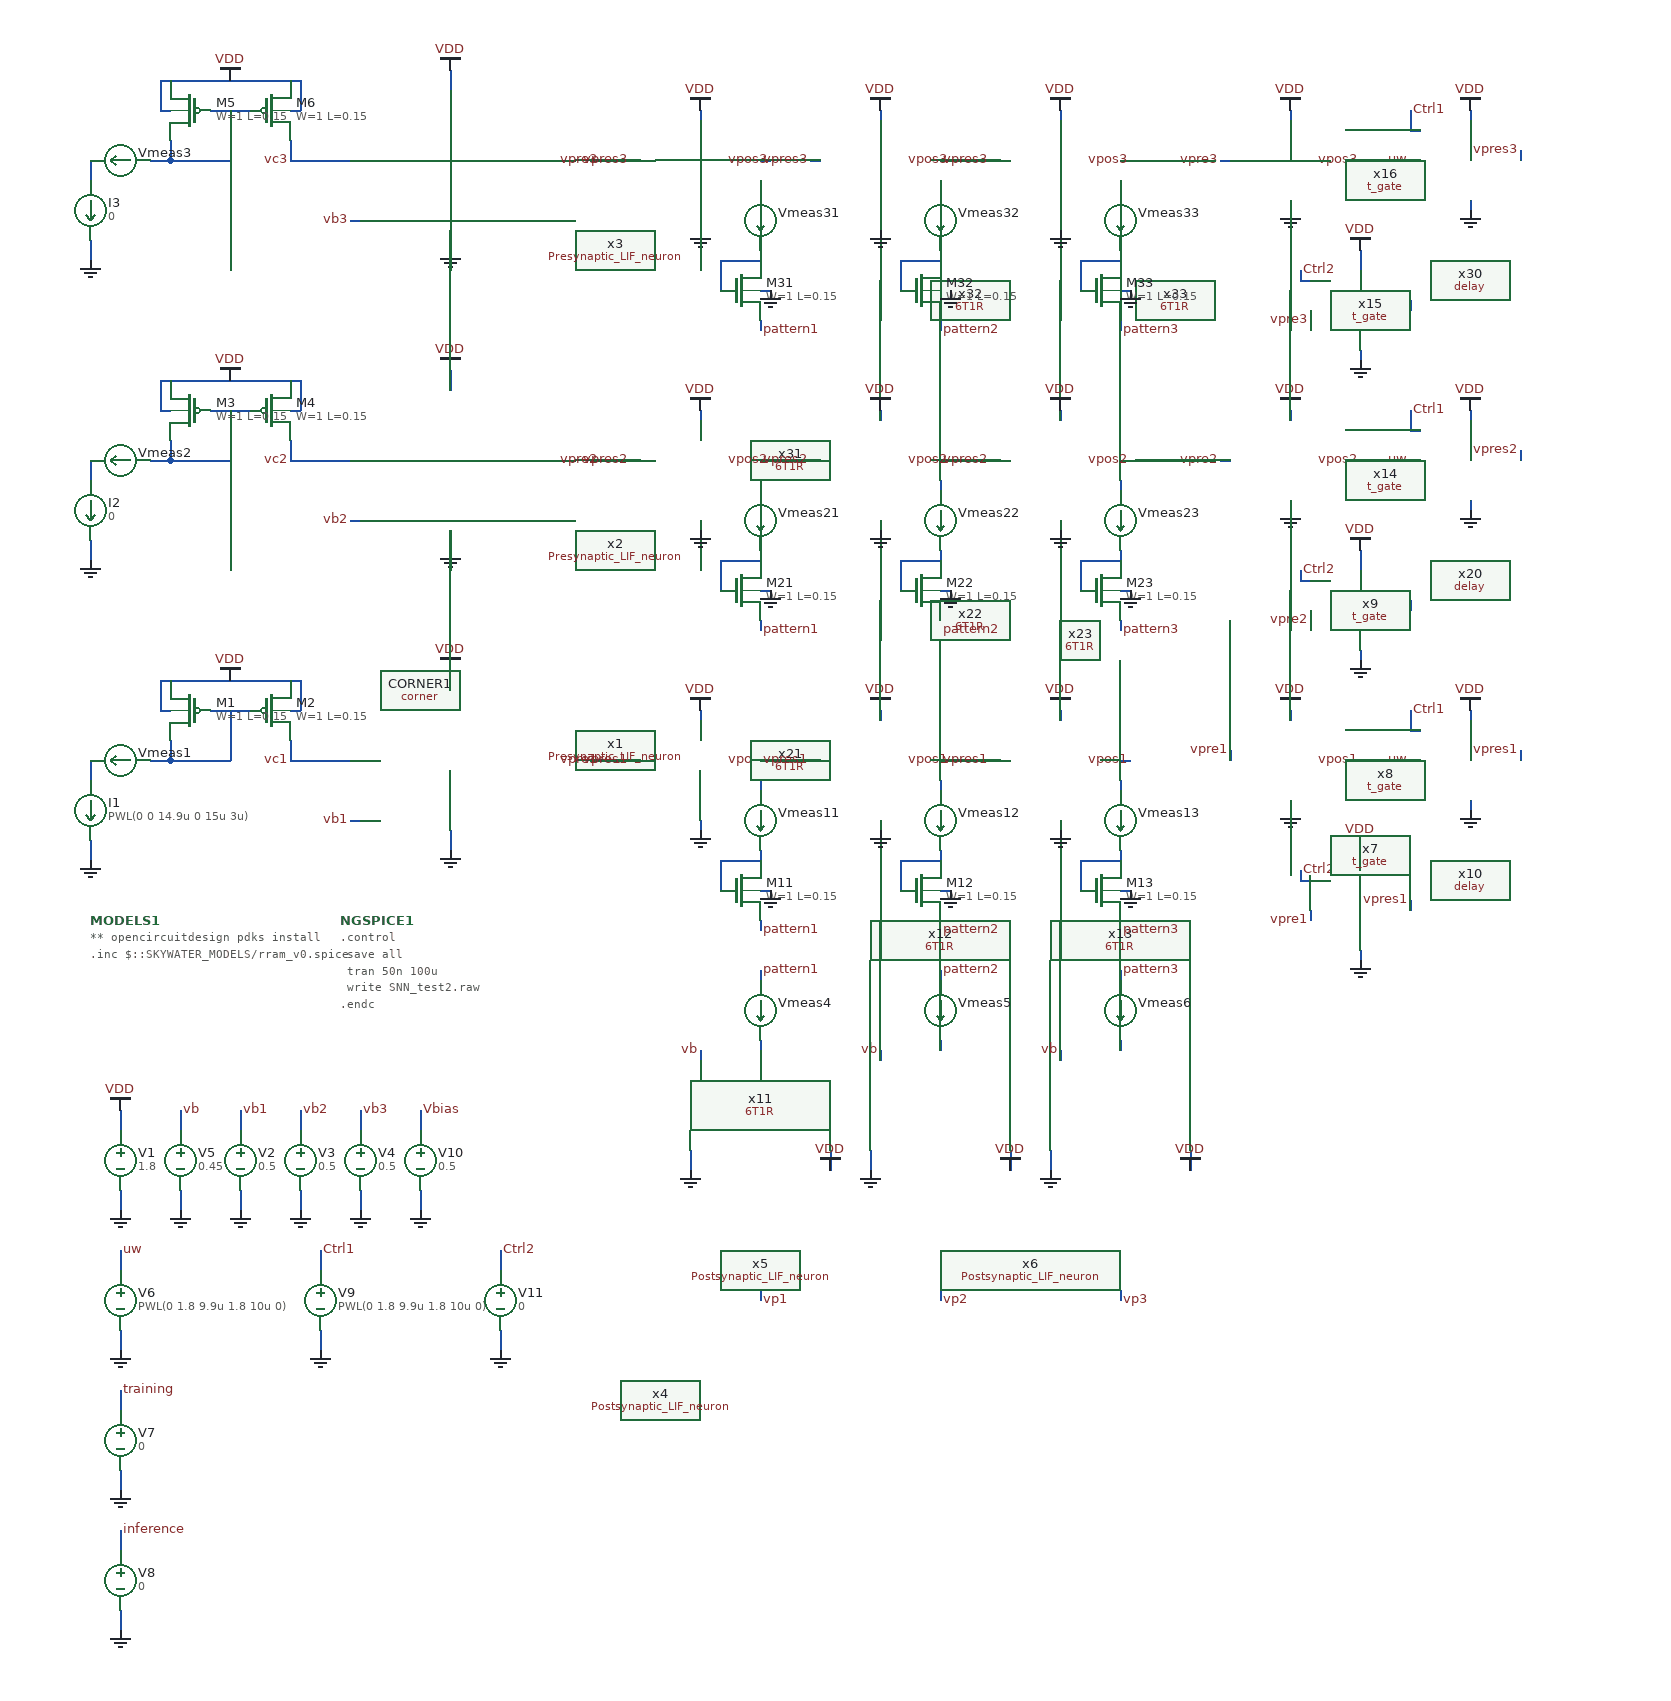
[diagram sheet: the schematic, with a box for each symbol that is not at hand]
v {xschem version=3.4.5 file_version=1.2
}
G {}
K {}
V {}
S {}
E {}
B 2 -1900 -1640 -1100 -1240 {flags=graph
y1=-0.081
y2=1.9
ypos1=0
ypos2=2
divy=5
subdivy=1
unity=1
x1=0
x2=0.0001
divx=5
subdivx=1
xlabmag=1.0
ylabmag=1.0
node="\\"Vpres1 [V];vpres1\\"
vpos1"
color="4 6"
dataset=-1
unitx=1
logx=0
logy=0
}
B 2 -1100 -1640 -300 -1240 {flags=graph
y1=5.1e-08
y2=3.4e-05
ypos1=0
ypos2=2
divy=5
subdivy=1
unity=1
x1=0
x2=0.0001
divx=5
subdivx=1
xlabmag=1.0
ylabmag=1.0


dataset=-1
unitx=1
logx=0
logy=0



color="4 10"
node="\\"Ipre1 (A);i(vmeas1)\\"
\\"Ipost (A);i(vmeas)\\""}
B 2 -1900 -1240 -1100 -840 {flags=graph
y1=0.023
y2=1.8
ypos1=0
ypos2=2
divy=5
subdivy=1
unity=1
x1=0
x2=0.0001
divx=5
subdivx=1
xlabmag=1.0
ylabmag=1.0


dataset=-1
unitx=1
logx=0
logy=0

color=4
node="\\"Vmempre1 [V];vc1\\""}
B 2 -1100 -1240 -300 -840 {flags=graph
y1=2.2
y2=3.4
ypos1=0
ypos2=2
divy=5
subdivy=1
unity=1
x1=0
x2=0.0001
divx=5
subdivx=1
xlabmag=1.0
ylabmag=1.0


dataset=-1
unitx=1
logx=0
logy=0




color=10
node="\\"Thickness1 [nm]; 5 n.x23.xr1.n1#ngap -\\""}
B 2 -1900 -840 -1100 -440 {flags=graph
y1=0
y2=1.8
ypos1=0
ypos2=2
divy=5
subdivy=1
unity=1
x1=0
x2=0.0001
divx=5
subdivx=1
xlabmag=1.0
ylabmag=1.0


dataset=-1
unitx=1
logx=0
logy=0
color="7 8 11 9"
node="\\"Update Weights;uw\\"
\\"Training;training\\"
\\"Inference;inference\\"
\\"e\\""}
B 2 -1100 -840 -300 -440 {flags=graph
y1=0
y2=0.01
ypos1=0
ypos2=2
divy=5
subdivy=1
unity=1
x1=0
x2=0.0001
divx=5
subdivx=1
xlabmag=1.0
ylabmag=1.0


dataset=-1
unitx=1
logx=0
logy=0

color="12 13 18"
node="\\"Pixel1;i(vmeas3)\\"
\\"Pixel2;i(vmeas3)\\"
\\"Pixel3;i(vmeas3)\\""}
N -3320 -530 -3320 -510 {
lab=GND}
N -3320 -610 -3320 -590 {
lab=VDD}
N -3200 -530 -3200 -510 {
lab=GND}
N -3200 -610 -3200 -590 {
lab=vb1}
N -2990 -890 -2990 -870 {
lab=GND}
N -2990 -1050 -2990 -1030 {
lab=VDD}
N -3090 -900 -3080 -900 {
lab=vb1}
N -3350 -880 -3350 -860 {
lab=GND}
N -3150 -980 -3150 -960 {
lab=vc1}
N -3150 -960 -3090 -960 {
lab=vc1}
N -3150 -1010 -3140 -1010 {
lab=VDD}
N -3140 -1040 -3140 -1010 {
lab=VDD}
N -3150 -1040 -3140 -1040 {
lab=VDD}
N -3230 -1010 -3190 -1010 {
lab=#net1}
N -3270 -1040 -3150 -1040 {
lab=VDD}
N -3280 -1010 -3270 -1010 {
lab=VDD}
N -3280 -1040 -3280 -1010 {
lab=VDD}
N -3280 -1040 -3270 -1040 {
lab=VDD}
N -3270 -980 -3270 -960 {
lab=#net1}
N -3270 -960 -3210 -960 {
lab=#net1}
N -3210 -1010 -3210 -960 {
lab=#net1}
N -3350 -960 -3350 -940 {
lab=#net2}
N -2560 -670 -2560 -660 {
lab=vb}
N -3140 -530 -3140 -510 {
lab=GND}
N -3140 -610 -3140 -590 {
lab=vb2}
N -3080 -530 -3080 -510 {
lab=GND}
N -3080 -610 -3080 -590 {
lab=vb3}
N -3260 -530 -3260 -510 {
lab=GND}
N -3260 -610 -3260 -590 {
lab=vb}
N -2990 -1190 -2990 -1170 {
lab=GND}
N -2990 -1350 -2990 -1330 {
lab=VDD}
N -3090 -1200 -3080 -1200 {
lab=vb2}
N -3150 -1260 -3090 -1260 {
lab=vc2}
N -3150 -1280 -3150 -1260 {
lab=vc2}
N -3150 -1310 -3140 -1310 {
lab=VDD}
N -3140 -1340 -3140 -1310 {
lab=VDD}
N -3150 -1340 -3140 -1340 {
lab=VDD}
N -3230 -1310 -3190 -1310 {
lab=#net3}
N -3270 -1340 -3150 -1340 {
lab=VDD}
N -3280 -1310 -3270 -1310 {
lab=VDD}
N -3280 -1340 -3280 -1310 {
lab=VDD}
N -3280 -1340 -3270 -1340 {
lab=VDD}
N -3270 -1280 -3270 -1260 {
lab=#net3}
N -3270 -1260 -3210 -1260 {
lab=#net3}
N -3210 -1310 -3210 -1260 {
lab=#net3}
N -2990 -1490 -2990 -1470 {
lab=GND}
N -2990 -1650 -2990 -1630 {
lab=VDD}
N -3090 -1500 -3080 -1500 {
lab=vb3}
N -3150 -1560 -3090 -1560 {
lab=vc3}
N -3150 -1580 -3150 -1560 {
lab=vc3}
N -3150 -1610 -3140 -1610 {
lab=VDD}
N -3140 -1640 -3140 -1610 {
lab=VDD}
N -3150 -1640 -3140 -1640 {
lab=VDD}
N -3230 -1610 -3190 -1610 {
lab=#net4}
N -3270 -1640 -3150 -1640 {
lab=VDD}
N -3280 -1610 -3270 -1610 {
lab=VDD}
N -3280 -1640 -3280 -1610 {
lab=VDD}
N -3280 -1640 -3270 -1640 {
lab=VDD}
N -3270 -1580 -3270 -1560 {
lab=#net4}
N -3270 -1560 -3210 -1560 {
lab=#net4}
N -3210 -1610 -3210 -1560 {
lab=#net4}
N -2740 -1500 -2740 -1490 {
lab=GND}
N -2740 -1610 -2740 -1600 {
lab=VDD}
N -2810 -1560 -2800 -1560 {
lab=vpres3}
N -2680 -1560 -2670 -1560 {
lab=vpos3}
N -2150 -1520 -2150 -1510 {
lab=GND}
N -2150 -1610 -2150 -1600 {
lab=VDD}
N -2090 -1560 -2080 -1560 {
lab=vpos3}
N -2220 -1560 -2210 -1560 {
lab=vpre3}
N -2740 -900 -2740 -890 {
lab=GND}
N -2740 -1010 -2740 -1000 {
lab=VDD}
N -2810 -960 -2800 -960 {
lab=vpres1}
N -2680 -960 -2670 -960 {
lab=vpos1}
N -2150 -920 -2150 -910 {
lab=GND}
N -2150 -1010 -2150 -1000 {
lab=VDD}
N -2090 -960 -2080 -960 {
lab=vpos1}
N -2740 -1200 -2740 -1190 {
lab=GND}
N -2740 -1310 -2740 -1300 {
lab=VDD}
N -2810 -1260 -2800 -1260 {
lab=vpres2}
N -2680 -1260 -2670 -1260 {
lab=vpos2}
N -2150 -1220 -2150 -1210 {
lab=GND}
N -2150 -1310 -2150 -1300 {
lab=VDD}
N -2090 -1260 -2080 -1260 {
lab=vpos2}
N -2220 -1260 -2210 -1260 {
lab=vpre2}
N -2560 -1500 -2560 -1490 {
lab=GND}
N -2560 -1610 -2560 -1600 {
lab=VDD}
N -2630 -1560 -2620 -1560 {
lab=vpres3}
N -2500 -1560 -2490 -1560 {
lab=vpos3}
N -2560 -900 -2560 -890 {
lab=GND}
N -2560 -1010 -2560 -1000 {
lab=VDD}
N -2630 -960 -2620 -960 {
lab=vpres1}
N -2500 -960 -2490 -960 {
lab=vpos1}
N -2560 -1200 -2560 -1190 {
lab=GND}
N -2560 -1310 -2560 -1300 {
lab=VDD}
N -2630 -1260 -2620 -1260 {
lab=vpres2}
N -2500 -1260 -2490 -1260 {
lab=vpos2}
N -2380 -1500 -2380 -1490 {
lab=GND}
N -2380 -1610 -2380 -1600 {
lab=VDD}
N -2450 -1560 -2440 -1560 {
lab=vpres3}
N -2320 -1560 -2310 -1560 {
lab=vpos3}
N -2380 -900 -2380 -890 {
lab=GND}
N -2380 -1010 -2380 -1000 {
lab=VDD}
N -2450 -960 -2440 -960 {
lab=vpres1}
N -2320 -960 -2310 -960 {
lab=vpos1}
N -2380 -1200 -2380 -1190 {
lab=GND}
N -2380 -1310 -2380 -1300 {
lab=VDD}
N -2450 -1260 -2440 -1260 {
lab=vpres2}
N -2320 -1260 -2310 -1260 {
lab=vpos2}
N -2680 -1540 -2680 -1530 {
lab=#net5}
N -2500 -1540 -2500 -1530 {
lab=#net6}
N -2320 -1540 -2320 -1530 {
lab=#net7}
N -2320 -1240 -2320 -1230 {
lab=#net8}
N -2500 -1240 -2500 -1230 {
lab=#net9}
N -2680 -1240 -2680 -1230 {
lab=#net10}
N -2680 -940 -2680 -930 {
lab=#net11}
N -2500 -940 -2500 -930 {
lab=#net12}
N -2320 -940 -2320 -930 {
lab=#net13}
N -2720 -860 -2720 -830 {
lab=#net14}
N -2720 -860 -2680 -860 {
lab=#net14}
N -2680 -830 -2670 -830 {
lab=GND}
N -2500 -830 -2490 -830 {
lab=GND}
N -2500 -870 -2500 -860 {
lab=#net15}
N -2540 -860 -2500 -860 {
lab=#net15}
N -2540 -860 -2540 -830 {
lab=#net15}
N -2680 -870 -2680 -860 {
lab=#net14}
N -2360 -860 -2360 -830 {
lab=#net16}
N -2360 -860 -2320 -860 {
lab=#net16}
N -2320 -830 -2310 -830 {
lab=GND}
N -2320 -870 -2320 -860 {
lab=#net16}
N -2720 -1160 -2720 -1130 {
lab=#net17}
N -2720 -1160 -2680 -1160 {
lab=#net17}
N -2680 -1130 -2670 -1130 {
lab=GND}
N -2680 -1170 -2680 -1160 {
lab=#net17}
N -2540 -1160 -2540 -1130 {
lab=#net18}
N -2540 -1160 -2500 -1160 {
lab=#net18}
N -2500 -1130 -2490 -1130 {
lab=GND}
N -2500 -1170 -2500 -1160 {
lab=#net18}
N -2360 -1160 -2360 -1130 {
lab=#net19}
N -2360 -1160 -2320 -1160 {
lab=#net19}
N -2320 -1130 -2310 -1130 {
lab=GND}
N -2320 -1170 -2320 -1160 {
lab=#net19}
N -2720 -1460 -2720 -1430 {
lab=#net20}
N -2720 -1460 -2680 -1460 {
lab=#net20}
N -2680 -1430 -2670 -1430 {
lab=GND}
N -2680 -1470 -2680 -1460 {
lab=#net20}
N -2540 -1460 -2540 -1430 {
lab=#net21}
N -2540 -1460 -2500 -1460 {
lab=#net21}
N -2500 -1430 -2490 -1430 {
lab=GND}
N -2500 -1470 -2500 -1460 {
lab=#net21}
N -2360 -1460 -2360 -1430 {
lab=#net22}
N -2360 -1460 -2320 -1460 {
lab=#net22}
N -2320 -1430 -2310 -1430 {
lab=GND}
N -2320 -1470 -2320 -1460 {
lab=#net22}
N -2680 -1400 -2680 -1390 {
lab=pattern1}
N -2680 -1100 -2680 -1090 {
lab=pattern1}
N -2680 -800 -2680 -790 {
lab=pattern1}
N -2500 -800 -2500 -790 {
lab=pattern2}
N -2320 -800 -2320 -790 {
lab=pattern3}
N -2320 -1100 -2320 -1090 {
lab=pattern3}
N -2320 -1400 -2320 -1390 {
lab=pattern3}
N -2500 -1100 -2500 -1090 {
lab=pattern2}
N -2500 -1400 -2500 -1390 {
lab=pattern2}
N -2500 -680 -2500 -670 {
lab=#net23}
N -2500 -750 -2500 -740 {
lab=pattern2}
N -2500 -430 -2500 -420 {
lab=vp2}
N -2740 -670 -2740 -660 {
lab=vb}
N -2680 -680 -2680 -670 {
lab=#net24}
N -2680 -750 -2680 -740 {
lab=pattern1}
N -2680 -430 -2680 -420 {
lab=vp1}
N -2380 -670 -2380 -660 {
lab=vb}
N -2320 -680 -2320 -670 {
lab=#net25}
N -2320 -750 -2320 -740 {
lab=pattern3}
N -2320 -430 -2320 -420 {
lab=vp3}
N -3320 -390 -3320 -370 {
lab=GND}
N -3320 -470 -3320 -450 {
lab=uw}
N -3320 -250 -3320 -230 {
lab=GND}
N -3320 -330 -3320 -310 {
lab=training}
N -2850 -1560 -2840 -1560 {
lab=vpre3}
N -2850 -1260 -2840 -1260 {
lab=vpre2}
N -2850 -960 -2840 -960 {
lab=vpre1}
N -2250 -570 -2250 -550 {
lab=VDD}
N -2390 -570 -2390 -550 {
lab=GND}
N -2750 -570 -2750 -550 {
lab=GND}
N -2610 -570 -2610 -550 {
lab=VDD}
N -2570 -570 -2570 -550 {
lab=GND}
N -3320 -110 -3320 -90 {
lab=GND}
N -3320 -190 -3320 -170 {
lab=inference}
N -2430 -570 -2430 -550 {
lab=VDD}
N -3290 -960 -3270 -960 {
lab=#net1}
N -3350 -1180 -3350 -1160 {
lab=GND}
N -3350 -1260 -3350 -1240 {
lab=#net26}
N -3290 -1260 -3270 -1260 {
lab=#net3}
N -3350 -1480 -3350 -1460 {
lab=GND}
N -3350 -1560 -3350 -1540 {
lab=#net27}
N -3290 -1560 -3270 -1560 {
lab=#net4}
N -3120 -390 -3120 -370 {
lab=GND}
N -3120 -470 -3120 -450 {
lab=Ctrl1}
N -1970 -920 -1970 -910 {
lab=GND}
N -1970 -1010 -1970 -1000 {
lab=VDD}
N -1920 -970 -1920 -960 {
lab=vpres1}
N -2210 -970 -2210 -960 {
lab=vpre1}
N -2030 -990 -2020 -990 {
lab=Ctrl1}
N -2080 -770 -2080 -760 {
lab=GND}
N -2030 -820 -2030 -810 {
lab=vpres1}
N -2130 -810 -2130 -800 {
lab=vpre1}
N -2140 -850 -2140 -840 {
lab=Ctrl2}
N -2140 -840 -2130 -840 {
lab=Ctrl2}
N -2940 -390 -2940 -370 {
lab=GND}
N -2940 -470 -2940 -450 {
lab=Ctrl2}
N -2080 -1070 -2080 -1060 {
lab=GND}
N -2030 -1120 -2030 -1110 {
lab=vpres2}
N -2130 -1110 -2130 -1100 {
lab=vpre2}
N -2140 -1150 -2140 -1140 {
lab=Ctrl2}
N -2140 -1140 -2130 -1140 {
lab=Ctrl2}
N -2080 -1370 -2080 -1360 {
lab=GND}
N -2030 -1420 -2030 -1410 {
lab=vpres3}
N -2130 -1410 -2130 -1400 {
lab=vpre3}
N -2140 -1450 -2140 -1440 {
lab=Ctrl2}
N -2140 -1440 -2130 -1440 {
lab=Ctrl2}
N -2080 -1170 -2080 -1150 {
lab=VDD}
N -2080 -1470 -2080 -1450 {
lab=VDD}
N -2080 -870 -2080 -850 {
lab=VDD}
N -2030 -960 -2020 -960 {
lab=uw}
N -2030 -1010 -2030 -990 {
lab=Ctrl1}
N -1970 -1220 -1970 -1210 {
lab=GND}
N -1970 -1310 -1970 -1300 {
lab=VDD}
N -1920 -1270 -1920 -1260 {
lab=vpres2}
N -2030 -1290 -2020 -1290 {
lab=Ctrl1}
N -2030 -1260 -2020 -1260 {
lab=uw}
N -2030 -1310 -2030 -1290 {
lab=Ctrl1}
N -1970 -1520 -1970 -1510 {
lab=GND}
N -1970 -1610 -1970 -1600 {
lab=VDD}
N -1920 -1570 -1920 -1560 {
lab=vpres3}
N -2030 -1590 -2020 -1590 {
lab=Ctrl1}
N -2030 -1560 -2020 -1560 {
lab=uw}
N -2030 -1610 -2030 -1590 {
lab=Ctrl1}
N -3020 -530 -3020 -510 {
lab=GND}
N -3020 -610 -3020 -590 {
lab=Vbias}
C {devices/vsource.sym} -3320 -560 0 0 {name=V1 value=1.8}
C {devices/gnd.sym} -3320 -510 0 0 {name=l6 lab=GND}
C {devices/vdd.sym} -3320 -610 0 0 {name=l7 lab=VDD}
C {devices/vsource.sym} -3200 -560 0 0 {name=V2 value=0.5}
C {devices/gnd.sym} -3200 -510 0 0 {name=l9 lab=GND}
C {devices/lab_pin.sym} -3200 -610 2 0 {name=p9 sig_type=std_logic lab=vb1}
C {devices/gnd.sym} -2990 -870 0 0 {name=l13 lab=GND}
C {devices/vdd.sym} -2990 -1050 0 0 {name=l14 lab=VDD}
C {devices/lab_pin.sym} -3090 -900 0 0 {name=p13 sig_type=std_logic lab=vb1}
C {devices/vdd.sym} -3210 -1040 0 0 {name=l19 lab=VDD}
C {devices/isource.sym} -3350 -910 0 1 {name=I1 value="PWL(0 0 14.9u 0 15u 3u)"}
C {devices/gnd.sym} -3350 -860 0 0 {name=l20 lab=GND}
C {sky130_fd_pr/pfet_01v8.sym} -3170 -1010 0 0 {name=M2
L=0.15
W=1
nf=1
mult=1
ad="'int((nf+1)/2) * W/nf * 0.29'" 
pd="'2*int((nf+1)/2) * (W/nf + 0.29)'"
as="'int((nf+2)/2) * W/nf * 0.29'" 
ps="'2*int((nf+2)/2) * (W/nf + 0.29)'"
nrd="'0.29 / W'" nrs="'0.29 / W'"
sa=0 sb=0 sd=0
model=pfet_01v8
spiceprefix=X
}
C {sky130_fd_pr/pfet_01v8.sym} -3250 -1010 0 1 {name=M1
L=0.15
W=1
nf=1
mult=1
ad="'int((nf+1)/2) * W/nf * 0.29'" 
pd="'2*int((nf+1)/2) * (W/nf + 0.29)'"
as="'int((nf+2)/2) * W/nf * 0.29'" 
ps="'2*int((nf+2)/2) * (W/nf + 0.29)'"
nrd="'0.29 / W'" nrs="'0.29 / W'"
sa=0 sb=0 sd=0
model=pfet_01v8
spiceprefix=X
}
C {devices/lab_pin.sym} -2560 -670 0 0 {name=p1 sig_type=std_logic lab=vb}
C {devices/gnd.sym} -2570 -550 0 0 {name=l1 lab=GND}
C {devices/vdd.sym} -2430 -550 2 0 {name=l2 lab=VDD}
C {devices/ammeter.sym} -2680 -1500 0 0 {name=Vmeas31 savecurrent=true}
C {devices/vsource.sym} -3140 -560 0 0 {name=V3 value=0.5}
C {devices/gnd.sym} -3140 -510 0 0 {name=l5 lab=GND}
C {devices/lab_pin.sym} -3140 -610 2 0 {name=p3 sig_type=std_logic lab=vb2}
C {devices/vsource.sym} -3080 -560 0 0 {name=V4 value=0.5}
C {devices/gnd.sym} -3080 -510 0 0 {name=l21 lab=GND}
C {devices/lab_pin.sym} -3080 -610 2 0 {name=p6 sig_type=std_logic lab=vb3}
C {/home/ricardo/RATT_repos/Proyectos_xschem/LIF_neuron/Presynaptic_LIF_neuron.sym} -2790 -860 0 0 {name=x1}
C {/home/ricardo/RATT_repos/Proyectos_xschem/LIF_neuron/Postsynaptic_LIF_neuron.sym} -2600 -320 1 0 {name=x5}
C {sky130_fd_pr/corner.sym} -3230 -800 0 0 {name=CORNER1 only_toplevel=true corner=tt}
C {devices/code.sym} -3350 -800 0 0 {name=MODELS1
only_toplevel=true
format="tcleval( @value )"
value="
** opencircuitdesign pdks install
.inc $::SKYWATER_MODELS/rram_v0.spice
"
spice_ignore=false}
C {devices/code_shown.sym} -3100 -800 0 0 {name=NGSPICE1
only_toplevel=true
value="
.control
  save all
  tran 50n 100u
  write SNN_test2.raw
.endc
" }
C {devices/launcher.sym} -3040 -670 0 0 {name=h1
descr="load waves" 
tclcommand="xschem raw_read $netlist_dir/SNN_test2.raw tran"
}
C {devices/lab_pin.sym} -3150 -960 0 0 {name=p10 sig_type=std_logic lab=vc1}
C {devices/vsource.sym} -3260 -560 0 0 {name=V5 value=0.45}
C {devices/gnd.sym} -3260 -510 0 0 {name=l29 lab=GND}
C {devices/lab_pin.sym} -3260 -610 2 0 {name=p16 sig_type=std_logic lab=vb}
C {devices/gnd.sym} -2990 -1170 0 0 {name=l8 lab=GND}
C {devices/vdd.sym} -2990 -1350 0 0 {name=l10 lab=VDD}
C {devices/lab_pin.sym} -3090 -1200 0 0 {name=p4 sig_type=std_logic lab=vb2}
C {/home/ricardo/RATT_repos/Proyectos_xschem/LIF_neuron/Presynaptic_LIF_neuron.sym} -2790 -1160 0 0 {name=x2}
C {devices/lab_pin.sym} -3150 -1260 0 0 {name=p7 sig_type=std_logic lab=vc2}
C {devices/vdd.sym} -3210 -1340 0 0 {name=l12 lab=VDD}
C {sky130_fd_pr/pfet_01v8.sym} -3170 -1310 0 0 {name=M4
L=0.15
W=1
nf=1
mult=1
ad="'int((nf+1)/2) * W/nf * 0.29'" 
pd="'2*int((nf+1)/2) * (W/nf + 0.29)'"
as="'int((nf+2)/2) * W/nf * 0.29'" 
ps="'2*int((nf+2)/2) * (W/nf + 0.29)'"
nrd="'0.29 / W'" nrs="'0.29 / W'"
sa=0 sb=0 sd=0
model=pfet_01v8
spiceprefix=X
}
C {sky130_fd_pr/pfet_01v8.sym} -3250 -1310 0 1 {name=M3
L=0.15
W=1
nf=1
mult=1
ad="'int((nf+1)/2) * W/nf * 0.29'" 
pd="'2*int((nf+1)/2) * (W/nf + 0.29)'"
as="'int((nf+2)/2) * W/nf * 0.29'" 
ps="'2*int((nf+2)/2) * (W/nf + 0.29)'"
nrd="'0.29 / W'" nrs="'0.29 / W'"
sa=0 sb=0 sd=0
model=pfet_01v8
spiceprefix=X
}
C {devices/gnd.sym} -2990 -1470 0 0 {name=l23 lab=GND}
C {devices/vdd.sym} -2990 -1650 0 0 {name=l24 lab=VDD}
C {devices/lab_pin.sym} -3090 -1500 0 0 {name=p12 sig_type=std_logic lab=vb3}
C {/home/ricardo/RATT_repos/Proyectos_xschem/synapse/6T1R.sym} -2680 -1380 0 0 {name=x31}
C {devices/vdd.sym} -2740 -1610 0 0 {name=l25 lab=VDD}
C {devices/gnd.sym} -2740 -1490 0 0 {name=l26 lab=GND}
C {/home/ricardo/RATT_repos/Proyectos_xschem/LIF_neuron/Presynaptic_LIF_neuron.sym} -2790 -1460 0 0 {name=x3}
C {devices/lab_pin.sym} -3150 -1560 0 0 {name=p18 sig_type=std_logic lab=vc3}
C {devices/vdd.sym} -3210 -1640 0 0 {name=l30 lab=VDD}
C {sky130_fd_pr/pfet_01v8.sym} -3170 -1610 0 0 {name=M6
L=0.15
W=1
nf=1
mult=1
ad="'int((nf+1)/2) * W/nf * 0.29'" 
pd="'2*int((nf+1)/2) * (W/nf + 0.29)'"
as="'int((nf+2)/2) * W/nf * 0.29'" 
ps="'2*int((nf+2)/2) * (W/nf + 0.29)'"
nrd="'0.29 / W'" nrs="'0.29 / W'"
sa=0 sb=0 sd=0
model=pfet_01v8
spiceprefix=X
}
C {sky130_fd_pr/pfet_01v8.sym} -3250 -1610 0 1 {name=M5
L=0.15
W=1
nf=1
mult=1
ad="'int((nf+1)/2) * W/nf * 0.29'" 
pd="'2*int((nf+1)/2) * (W/nf + 0.29)'"
as="'int((nf+2)/2) * W/nf * 0.29'" 
ps="'2*int((nf+2)/2) * (W/nf + 0.29)'"
nrd="'0.29 / W'" nrs="'0.29 / W'"
sa=0 sb=0 sd=0
model=pfet_01v8
spiceprefix=X
}
C {/home/ricardo/RATT_repos/Proyectos_xschem/delay/delay.sym} -1970 -1440 0 0 {name=x30}
C {devices/lab_pin.sym} -2810 -1560 1 0 {name=p19 sig_type=std_logic lab=vpres3}
C {devices/lab_pin.sym} -2670 -1560 1 0 {name=p22 sig_type=std_logic lab=vpos3}
C {devices/gnd.sym} -2150 -1510 0 0 {name=l36 lab=GND}
C {devices/vdd.sym} -2150 -1610 0 0 {name=l37 lab=VDD}
C {devices/lab_pin.sym} -2080 -1560 1 0 {name=p23 sig_type=std_logic lab=vpos3}
C {devices/lab_pin.sym} -2220 -1560 1 0 {name=p25 sig_type=std_logic lab=vpre3}
C {/home/ricardo/RATT_repos/Proyectos_xschem/synapse/6T1R.sym} -2680 -780 0 0 {name=x11}
C {devices/vdd.sym} -2740 -1010 0 0 {name=l38 lab=VDD}
C {devices/gnd.sym} -2740 -890 0 0 {name=l39 lab=GND}
C {/home/ricardo/RATT_repos/Proyectos_xschem/delay/delay.sym} -1970 -840 0 0 {name=x10}
C {devices/lab_pin.sym} -2810 -960 1 0 {name=p26 sig_type=std_logic lab=vpres1}
C {devices/lab_pin.sym} -2670 -960 1 0 {name=p27 sig_type=std_logic lab=vpos1}
C {devices/gnd.sym} -2150 -910 0 0 {name=l40 lab=GND}
C {devices/vdd.sym} -2150 -1010 0 0 {name=l42 lab=VDD}
C {devices/lab_pin.sym} -2080 -960 1 0 {name=p28 sig_type=std_logic lab=vpos1}
C {devices/lab_pin.sym} -2210 -970 1 0 {name=p33 sig_type=std_logic lab=vpre1}
C {/home/ricardo/RATT_repos/Proyectos_xschem/synapse/6T1R.sym} -2680 -1080 0 0 {name=x21}
C {devices/vdd.sym} -2740 -1310 0 0 {name=l43 lab=VDD}
C {devices/gnd.sym} -2740 -1190 0 0 {name=l44 lab=GND}
C {/home/ricardo/RATT_repos/Proyectos_xschem/delay/delay.sym} -1970 -1140 0 0 {name=x20}
C {devices/lab_pin.sym} -2810 -1260 1 0 {name=p34 sig_type=std_logic lab=vpres2}
C {devices/lab_pin.sym} -2670 -1260 1 0 {name=p35 sig_type=std_logic lab=vpos2}
C {devices/gnd.sym} -2150 -1210 0 0 {name=l45 lab=GND}
C {devices/vdd.sym} -2150 -1310 0 0 {name=l50 lab=VDD}
C {devices/lab_pin.sym} -2080 -1260 1 0 {name=p36 sig_type=std_logic lab=vpos2}
C {devices/lab_pin.sym} -2220 -1260 1 0 {name=p37 sig_type=std_logic lab=vpre2}
C {/home/ricardo/RATT_repos/Proyectos_xschem/synapse/6T1R.sym} -2500 -1380 0 0 {name=x32}
C {devices/vdd.sym} -2560 -1610 0 0 {name=l3 lab=VDD}
C {devices/gnd.sym} -2560 -1490 0 0 {name=l11 lab=GND}
C {devices/lab_pin.sym} -2630 -1560 1 0 {name=p8 sig_type=std_logic lab=vpres3}
C {devices/lab_pin.sym} -2490 -1560 1 0 {name=p11 sig_type=std_logic lab=vpos3}
C {/home/ricardo/RATT_repos/Proyectos_xschem/synapse/6T1R.sym} -2500 -780 0 0 {name=x12}
C {devices/vdd.sym} -2560 -1010 0 0 {name=l16 lab=VDD}
C {devices/gnd.sym} -2560 -890 0 0 {name=l17 lab=GND}
C {devices/lab_pin.sym} -2630 -960 1 0 {name=p29 sig_type=std_logic lab=vpres1}
C {devices/lab_pin.sym} -2490 -960 1 0 {name=p30 sig_type=std_logic lab=vpos1}
C {/home/ricardo/RATT_repos/Proyectos_xschem/synapse/6T1R.sym} -2500 -1080 0 0 {name=x22}
C {devices/vdd.sym} -2560 -1310 0 0 {name=l46 lab=VDD}
C {devices/gnd.sym} -2560 -1190 0 0 {name=l47 lab=GND}
C {devices/lab_pin.sym} -2630 -1260 1 0 {name=p31 sig_type=std_logic lab=vpres2}
C {devices/lab_pin.sym} -2490 -1260 1 0 {name=p32 sig_type=std_logic lab=vpos2}
C {/home/ricardo/RATT_repos/Proyectos_xschem/synapse/6T1R.sym} -2320 -1380 0 0 {name=x33}
C {devices/vdd.sym} -2380 -1610 0 0 {name=l48 lab=VDD}
C {devices/gnd.sym} -2380 -1490 0 0 {name=l49 lab=GND}
C {devices/lab_pin.sym} -2450 -1560 1 0 {name=p38 sig_type=std_logic lab=vpres3}
C {devices/lab_pin.sym} -2310 -1560 1 0 {name=p39 sig_type=std_logic lab=vpos3}
C {/home/ricardo/RATT_repos/Proyectos_xschem/synapse/6T1R.sym} -2320 -780 0 0 {name=x13}
C {devices/vdd.sym} -2380 -1010 0 0 {name=l51 lab=VDD}
C {devices/gnd.sym} -2380 -890 0 0 {name=l52 lab=GND}
C {devices/lab_pin.sym} -2450 -960 1 0 {name=p40 sig_type=std_logic lab=vpres1}
C {devices/lab_pin.sym} -2310 -960 1 0 {name=p41 sig_type=std_logic lab=vpos1}
C {/home/ricardo/RATT_repos/Proyectos_xschem/synapse/6T1R.sym} -2320 -1080 0 0 {name=x23}
C {devices/vdd.sym} -2380 -1310 0 0 {name=l53 lab=VDD}
C {devices/gnd.sym} -2380 -1190 0 0 {name=l54 lab=GND}
C {devices/lab_pin.sym} -2450 -1260 1 0 {name=p42 sig_type=std_logic lab=vpres2}
C {devices/lab_pin.sym} -2310 -1260 1 0 {name=p43 sig_type=std_logic lab=vpos2}
C {devices/ammeter.sym} -2500 -1500 0 0 {name=Vmeas32 savecurrent=true}
C {devices/ammeter.sym} -2320 -1500 0 0 {name=Vmeas33 savecurrent=true}
C {devices/ammeter.sym} -2320 -1200 0 0 {name=Vmeas23 savecurrent=true}
C {devices/ammeter.sym} -2500 -1200 0 0 {name=Vmeas22 savecurrent=true}
C {devices/ammeter.sym} -2680 -1200 0 0 {name=Vmeas21 savecurrent=true}
C {devices/ammeter.sym} -2680 -900 0 0 {name=Vmeas11 savecurrent=true}
C {devices/ammeter.sym} -2500 -900 0 0 {name=Vmeas12 savecurrent=true}
C {devices/ammeter.sym} -2320 -900 0 0 {name=Vmeas13 savecurrent=true}
C {sky130_fd_pr/nfet_01v8.sym} -2700 -830 0 0 {name=M11
L=0.15
W=1
nf=1 
mult=1
ad="'int((nf+1)/2) * W/nf * 0.29'" 
pd="'2*int((nf+1)/2) * (W/nf + 0.29)'"
as="'int((nf+2)/2) * W/nf * 0.29'" 
ps="'2*int((nf+2)/2) * (W/nf + 0.29)'"
nrd="'0.29 / W'" nrs="'0.29 / W'"
sa=0 sb=0 sd=0
model=nfet_01v8
spiceprefix=X
}
C {devices/gnd.sym} -2670 -830 3 0 {name=l4 lab=GND}
C {sky130_fd_pr/nfet_01v8.sym} -2520 -830 0 0 {name=M12
L=0.15
W=1
nf=1 
mult=1
ad="'int((nf+1)/2) * W/nf * 0.29'" 
pd="'2*int((nf+1)/2) * (W/nf + 0.29)'"
as="'int((nf+2)/2) * W/nf * 0.29'" 
ps="'2*int((nf+2)/2) * (W/nf + 0.29)'"
nrd="'0.29 / W'" nrs="'0.29 / W'"
sa=0 sb=0 sd=0
model=nfet_01v8
spiceprefix=X
}
C {devices/gnd.sym} -2490 -830 3 0 {name=l18 lab=GND}
C {sky130_fd_pr/nfet_01v8.sym} -2340 -830 0 0 {name=M13
L=0.15
W=1
nf=1 
mult=1
ad="'int((nf+1)/2) * W/nf * 0.29'" 
pd="'2*int((nf+1)/2) * (W/nf + 0.29)'"
as="'int((nf+2)/2) * W/nf * 0.29'" 
ps="'2*int((nf+2)/2) * (W/nf + 0.29)'"
nrd="'0.29 / W'" nrs="'0.29 / W'"
sa=0 sb=0 sd=0
model=nfet_01v8
spiceprefix=X
}
C {devices/gnd.sym} -2310 -830 3 0 {name=l22 lab=GND}
C {sky130_fd_pr/nfet_01v8.sym} -2700 -1130 0 0 {name=M21
L=0.15
W=1
nf=1 
mult=1
ad="'int((nf+1)/2) * W/nf * 0.29'" 
pd="'2*int((nf+1)/2) * (W/nf + 0.29)'"
as="'int((nf+2)/2) * W/nf * 0.29'" 
ps="'2*int((nf+2)/2) * (W/nf + 0.29)'"
nrd="'0.29 / W'" nrs="'0.29 / W'"
sa=0 sb=0 sd=0
model=nfet_01v8
spiceprefix=X
}
C {devices/gnd.sym} -2670 -1130 3 0 {name=l27 lab=GND}
C {sky130_fd_pr/nfet_01v8.sym} -2520 -1130 0 0 {name=M22
L=0.15
W=1
nf=1 
mult=1
ad="'int((nf+1)/2) * W/nf * 0.29'" 
pd="'2*int((nf+1)/2) * (W/nf + 0.29)'"
as="'int((nf+2)/2) * W/nf * 0.29'" 
ps="'2*int((nf+2)/2) * (W/nf + 0.29)'"
nrd="'0.29 / W'" nrs="'0.29 / W'"
sa=0 sb=0 sd=0
model=nfet_01v8
spiceprefix=X
}
C {devices/gnd.sym} -2490 -1130 3 0 {name=l28 lab=GND}
C {sky130_fd_pr/nfet_01v8.sym} -2340 -1130 0 0 {name=M23
L=0.15
W=1
nf=1 
mult=1
ad="'int((nf+1)/2) * W/nf * 0.29'" 
pd="'2*int((nf+1)/2) * (W/nf + 0.29)'"
as="'int((nf+2)/2) * W/nf * 0.29'" 
ps="'2*int((nf+2)/2) * (W/nf + 0.29)'"
nrd="'0.29 / W'" nrs="'0.29 / W'"
sa=0 sb=0 sd=0
model=nfet_01v8
spiceprefix=X
}
C {devices/gnd.sym} -2310 -1130 3 0 {name=l55 lab=GND}
C {sky130_fd_pr/nfet_01v8.sym} -2700 -1430 0 0 {name=M31
L=0.15
W=1
nf=1 
mult=1
ad="'int((nf+1)/2) * W/nf * 0.29'" 
pd="'2*int((nf+1)/2) * (W/nf + 0.29)'"
as="'int((nf+2)/2) * W/nf * 0.29'" 
ps="'2*int((nf+2)/2) * (W/nf + 0.29)'"
nrd="'0.29 / W'" nrs="'0.29 / W'"
sa=0 sb=0 sd=0
model=nfet_01v8
spiceprefix=X
}
C {devices/gnd.sym} -2670 -1430 3 0 {name=l56 lab=GND}
C {sky130_fd_pr/nfet_01v8.sym} -2520 -1430 0 0 {name=M32
L=0.15
W=1
nf=1 
mult=1
ad="'int((nf+1)/2) * W/nf * 0.29'" 
pd="'2*int((nf+1)/2) * (W/nf + 0.29)'"
as="'int((nf+2)/2) * W/nf * 0.29'" 
ps="'2*int((nf+2)/2) * (W/nf + 0.29)'"
nrd="'0.29 / W'" nrs="'0.29 / W'"
sa=0 sb=0 sd=0
model=nfet_01v8
spiceprefix=X
}
C {devices/gnd.sym} -2490 -1430 3 0 {name=l57 lab=GND}
C {sky130_fd_pr/nfet_01v8.sym} -2340 -1430 0 0 {name=M33
L=0.15
W=1
nf=1 
mult=1
ad="'int((nf+1)/2) * W/nf * 0.29'" 
pd="'2*int((nf+1)/2) * (W/nf + 0.29)'"
as="'int((nf+2)/2) * W/nf * 0.29'" 
ps="'2*int((nf+2)/2) * (W/nf + 0.29)'"
nrd="'0.29 / W'" nrs="'0.29 / W'"
sa=0 sb=0 sd=0
model=nfet_01v8
spiceprefix=X
}
C {devices/gnd.sym} -2310 -1430 3 0 {name=l58 lab=GND}
C {devices/lab_pin.sym} -2680 -1390 2 0 {name=p44 sig_type=std_logic lab=pattern1}
C {devices/lab_pin.sym} -2680 -1090 2 0 {name=p45 sig_type=std_logic lab=pattern1}
C {devices/lab_pin.sym} -2680 -790 2 0 {name=p46 sig_type=std_logic lab=pattern1}
C {devices/lab_pin.sym} -2500 -790 2 0 {name=p47 sig_type=std_logic lab=pattern2}
C {devices/lab_pin.sym} -2320 -790 2 0 {name=p48 sig_type=std_logic lab=pattern3}
C {devices/lab_pin.sym} -2320 -1090 2 0 {name=p49 sig_type=std_logic lab=pattern3}
C {devices/lab_pin.sym} -2320 -1390 2 0 {name=p50 sig_type=std_logic lab=pattern3}
C {devices/lab_pin.sym} -2500 -1090 2 0 {name=p51 sig_type=std_logic lab=pattern2}
C {devices/lab_pin.sym} -2500 -1390 2 0 {name=p52 sig_type=std_logic lab=pattern2}
C {devices/lab_pin.sym} -1920 -970 1 0 {name=p24 sig_type=std_logic lab=vpres1}
C {devices/lab_pin.sym} -2030 -960 0 0 {name=p53 sig_type=std_logic lab=uw}
C {devices/ammeter.sym} -2500 -710 0 0 {name=Vmeas5 savecurrent=true}
C {devices/lab_pin.sym} -2500 -750 2 0 {name=p15 sig_type=std_logic lab=pattern2}
C {devices/lab_pin.sym} -2500 -420 2 0 {name=p58 sig_type=std_logic lab=vp2}
C {devices/lab_pin.sym} -2740 -670 0 0 {name=p59 sig_type=std_logic lab=vb}
C {devices/gnd.sym} -2750 -550 0 0 {name=l63 lab=GND}
C {devices/vdd.sym} -2610 -550 2 0 {name=l64 lab=VDD}
C {/home/ricardo/RATT_repos/Proyectos_xschem/LIF_neuron/Postsynaptic_LIF_neuron.sym} -2780 -320 1 0 {name=x4}
C {devices/ammeter.sym} -2680 -710 0 0 {name=Vmeas4 savecurrent=true}
C {devices/lab_pin.sym} -2680 -750 2 0 {name=p60 sig_type=std_logic lab=pattern1}
C {devices/lab_pin.sym} -2680 -420 2 0 {name=p61 sig_type=std_logic lab=vp1}
C {devices/lab_pin.sym} -2380 -670 0 0 {name=p62 sig_type=std_logic lab=vb}
C {devices/gnd.sym} -2390 -550 0 0 {name=l65 lab=GND}
C {devices/vdd.sym} -2250 -550 2 0 {name=l66 lab=VDD}
C {/home/ricardo/RATT_repos/Proyectos_xschem/LIF_neuron/Postsynaptic_LIF_neuron.sym} -2420 -320 1 0 {name=x6}
C {devices/ammeter.sym} -2320 -710 0 0 {name=Vmeas6 savecurrent=true}
C {devices/lab_pin.sym} -2320 -750 2 0 {name=p63 sig_type=std_logic lab=pattern3}
C {devices/lab_pin.sym} -2320 -420 2 0 {name=p64 sig_type=std_logic lab=vp3}
C {devices/vsource.sym} -3320 -420 0 0 {name=V6 value="PWL(0 1.8 9.9u 1.8 10u 0)"}
C {devices/gnd.sym} -3320 -370 0 0 {name=l67 lab=GND}
C {devices/lab_pin.sym} -3320 -470 2 0 {name=p65 sig_type=std_logic lab=uw}
C {devices/vsource.sym} -3320 -280 0 0 {name=V7 value=0}
C {devices/gnd.sym} -3320 -230 0 0 {name=l68 lab=GND}
C {devices/lab_pin.sym} -3320 -330 2 0 {name=p66 sig_type=std_logic lab=training}
C {devices/lab_pin.sym} -2840 -1560 1 0 {name=p67 sig_type=std_logic lab=vpre3}
C {devices/lab_pin.sym} -2840 -1260 1 0 {name=p68 sig_type=std_logic lab=vpre2}
C {devices/lab_pin.sym} -2840 -960 1 0 {name=p69 sig_type=std_logic lab=vpre1}
C {devices/vsource.sym} -3320 -140 0 0 {name=V8 value=0}
C {devices/gnd.sym} -3320 -90 0 0 {name=l69 lab=GND}
C {devices/lab_pin.sym} -3320 -190 2 0 {name=p73 sig_type=std_logic lab=inference}
C {devices/ammeter.sym} -3320 -960 1 0 {name=Vmeas1 savecurrent=true}
C {devices/isource.sym} -3350 -1210 0 1 {name=I2 value=0}
C {devices/gnd.sym} -3350 -1160 0 0 {name=l15 lab=GND}
C {devices/ammeter.sym} -3320 -1260 1 0 {name=Vmeas2 savecurrent=true}
C {devices/isource.sym} -3350 -1510 0 1 {name=I3 value=0}
C {devices/gnd.sym} -3350 -1460 0 0 {name=l31 lab=GND}
C {devices/ammeter.sym} -3320 -1560 1 0 {name=Vmeas3 savecurrent=true}
C {devices/lab_pin.sym} -2030 -1010 2 0 {name=p74 sig_type=std_logic lab=Ctrl1}
C {devices/vsource.sym} -3120 -420 0 0 {name=V9 value="PWL(0 1.8 9.9u 1.8 10u 0)"}
C {devices/gnd.sym} -3120 -370 0 0 {name=l72 lab=GND}
C {devices/lab_pin.sym} -3120 -470 2 0 {name=p75 sig_type=std_logic lab=Ctrl1}
C {devices/gnd.sym} -1970 -910 0 0 {name=l32 lab=GND}
C {devices/vdd.sym} -1970 -1010 0 0 {name=l41 lab=VDD}
C {devices/lab_pin.sym} -2030 -820 1 0 {name=p2 sig_type=std_logic lab=vpres1}
C {devices/lab_pin.sym} -2130 -800 3 0 {name=p5 sig_type=std_logic lab=vpre1}
C {devices/lab_pin.sym} -2140 -850 2 0 {name=p14 sig_type=std_logic lab=Ctrl2}
C {devices/gnd.sym} -2080 -760 0 0 {name=l33 lab=GND}
C {devices/vsource.sym} -2940 -420 0 0 {name=V11 value=0}
C {devices/gnd.sym} -2940 -370 0 0 {name=l35 lab=GND}
C {devices/lab_pin.sym} -2940 -470 2 0 {name=p17 sig_type=std_logic lab=Ctrl2}
C {devices/lab_pin.sym} -2030 -1120 1 0 {name=p20 sig_type=std_logic lab=vpres2}
C {devices/lab_pin.sym} -2130 -1100 3 0 {name=p21 sig_type=std_logic lab=vpre2}
C {devices/lab_pin.sym} -2140 -1150 2 0 {name=p70 sig_type=std_logic lab=Ctrl2}
C {devices/gnd.sym} -2080 -1060 0 0 {name=l71 lab=GND}
C {devices/lab_pin.sym} -2030 -1420 1 0 {name=p71 sig_type=std_logic lab=vpres3}
C {devices/lab_pin.sym} -2130 -1400 3 0 {name=p72 sig_type=std_logic lab=vpre3}
C {devices/lab_pin.sym} -2140 -1450 2 0 {name=p79 sig_type=std_logic lab=Ctrl2}
C {devices/gnd.sym} -2080 -1360 0 0 {name=l74 lab=GND}
C {devices/vdd.sym} -2080 -1470 0 0 {name=l34 lab=VDD}
C {devices/vdd.sym} -2080 -1170 0 0 {name=l70 lab=VDD}
C {devices/vdd.sym} -2080 -870 0 0 {name=l73 lab=VDD}
C {/home/ricardo/RATT_repos/Proyectos_xschem/switch/t_gate.sym} -2080 -810 0 0 {name=x7}
C {/home/ricardo/RATT_repos/Proyectos_xschem/switch/t_gate.sym} -2080 -1110 0 0 {name=x9}
C {/home/ricardo/RATT_repos/Proyectos_xschem/switch/t_gate.sym} -2080 -1410 0 0 {name=x15}
C {devices/lab_pin.sym} -1920 -1270 1 0 {name=p54 sig_type=std_logic lab=vpres2}
C {devices/lab_pin.sym} -2030 -1260 0 0 {name=p55 sig_type=std_logic lab=uw}
C {devices/lab_pin.sym} -2030 -1310 2 0 {name=p56 sig_type=std_logic lab=Ctrl1}
C {devices/gnd.sym} -1970 -1210 0 0 {name=l59 lab=GND}
C {devices/vdd.sym} -1970 -1310 0 0 {name=l60 lab=VDD}
C {devices/lab_pin.sym} -1920 -1570 1 0 {name=p76 sig_type=std_logic lab=vpres3}
C {devices/lab_pin.sym} -2030 -1560 0 0 {name=p77 sig_type=std_logic lab=uw}
C {devices/lab_pin.sym} -2030 -1610 2 0 {name=p80 sig_type=std_logic lab=Ctrl1}
C {devices/gnd.sym} -1970 -1510 0 0 {name=l61 lab=GND}
C {devices/vdd.sym} -1970 -1610 0 0 {name=l62 lab=VDD}
C {devices/vsource.sym} -3020 -560 0 0 {name=V10 value=0.5}
C {devices/gnd.sym} -3020 -510 0 0 {name=l75 lab=GND}
C {devices/lab_pin.sym} -3020 -610 2 0 {name=p82 sig_type=std_logic lab=Vbias}
C {/home/ricardo/RATT_repos/Proyectos_xschem/switch/t_gate.sym} -1970 -960 0 0 {name=x8}
C {/home/ricardo/RATT_repos/Proyectos_xschem/switch/t_gate.sym} -1970 -1260 0 0 {name=x14}
C {/home/ricardo/RATT_repos/Proyectos_xschem/switch/t_gate.sym} -1970 -1560 0 0 {name=x16}
